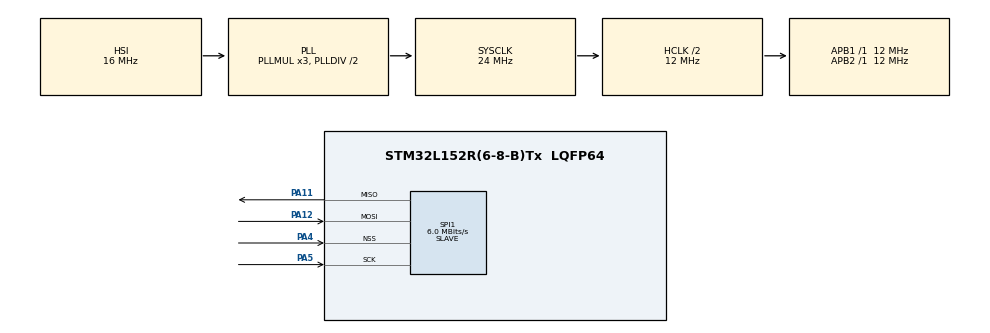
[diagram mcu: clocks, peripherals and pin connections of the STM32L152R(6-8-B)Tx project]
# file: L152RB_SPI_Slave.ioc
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Mcu.Family=STM32L1
Mcu.Name=STM32L152R(6-8-B)Tx
Mcu.Package=LQFP64
NVIC.PriorityGroup=NVIC_PRIORITYGROUP_4
NVIC.SPI1_IRQn=true\:0\:0\:false\:false\:true\:true\:true
PA11.Mode=Full_Duplex_Slave
PA11.Signal=SPI1_MISO
PA12.Mode=Full_Duplex_Slave
PA12.Signal=SPI1_MOSI
PA4.Mode=NSS_Signal_Hard_Input
PA4.Signal=SPI1_NSS
PA5.Mode=Full_Duplex_Slave
PA5.Signal=SPI1_SCK
ProjectManager.HeapSize=0x200
ProjectManager.StackSize=0x400
ProjectManager.TargetToolchain=STM32CubeIDE
RCC.AHBCLKDivider=RCC_SYSCLK_DIV2
RCC.AHBFreq_Value=12000000
RCC.APB1Freq_Value=12000000
RCC.APB1TimFreq_Value=12000000
RCC.APB2Freq_Value=12000000
RCC.APB2TimFreq_Value=12000000
RCC.HCLKFreq_Value=12000000
RCC.HSE_VALUE=24000000
RCC.HSI_VALUE=16000000
RCC.LSE_VALUE=32768
RCC.MSI_VALUE=2097000
RCC.SYSCLKFreq_VALUE=24000000
RCC.SYSCLKSource=RCC_SYSCLKSOURCE_PLLCLK
RCC.VCOOutputFreq_Value=48000000
SPI1.CalculateBaudRate=6.0 MBits/s
SPI1.Direction=SPI_DIRECTION_2LINES
SPI1.Mode=SPI_MODE_SLAVE
SPI1.VirtualNSS=VM_NSSHARD
SPI1.VirtualType=VM_SLAVE
board=custom

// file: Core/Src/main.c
/* USER CODE BEGIN Header */
/**
  ******************************************************************************
  * @file           : main.c
  * @brief          : Main program body
  ******************************************************************************
  * @attention
  *
  * <h2><center>&copy; Copyright (c) 2020 STMicroelectronics.
  * All rights reserved.</center></h2>
  *
  * This software component is licensed by ST under BSD 3-Clause license,
  * the "License"; You may not use this file except in compliance with the
  * License. You may obtain a copy of the License at:
  *                        opensource.org/licenses/BSD-3-Clause
  *
  ******************************************************************************
  */
/* USER CODE END Header */
#include "main.h"

SPI_HandleTypeDef hspi1;
uint8_t pData = 0;

void SystemClock_Config(void);
static void MX_GPIO_Init(void);
static void MX_SPI1_Init(void);

int main(void)
{
	HAL_Init();

	SystemClock_Config();

	MX_GPIO_Init();
	MX_SPI1_Init();

	HAL_SPI_Receive_IT(&hspi1, &pData, 1);

	while (1)
	{
		//HAL_SPI_Receive_IT(&hspi1, &pData, 1);
		HAL_GPIO_TogglePin(GPIOB, GPIO_PIN_6);
		HAL_Delay(500);
	}
}

void HAL_SPI_TxRxCpltCallback(SPI_HandleTypeDef *hspi)
{
	HAL_GPIO_TogglePin(GPIOB, GPIO_PIN_7);
	if(hspi->Instance == hspi1.Instance)
	{
		HAL_SPI_Receive_IT(&hspi1, &pData, 1);
	}
}

void SystemClock_Config(void)
{
  RCC_OscInitTypeDef RCC_OscInitStruct = {0};
  RCC_ClkInitTypeDef RCC_ClkInitStruct = {0};

  /** Configure the main internal regulator output voltage
  */
  __HAL_PWR_VOLTAGESCALING_CONFIG(PWR_REGULATOR_VOLTAGE_SCALE1);
  /** Initializes the RCC Oscillators according to the specified parameters
  * in the RCC_OscInitTypeDef structure.
  */
  RCC_OscInitStruct.OscillatorType = RCC_OSCILLATORTYPE_HSI;
  RCC_OscInitStruct.HSIState = RCC_HSI_ON;
  RCC_OscInitStruct.HSICalibrationValue = RCC_HSICALIBRATION_DEFAULT;
  RCC_OscInitStruct.PLL.PLLState = RCC_PLL_ON;
  RCC_OscInitStruct.PLL.PLLSource = RCC_PLLSOURCE_HSI;
  RCC_OscInitStruct.PLL.PLLMUL = RCC_PLL_MUL3;
  RCC_OscInitStruct.PLL.PLLDIV = RCC_PLL_DIV2;
  if (HAL_RCC_OscConfig(&RCC_OscInitStruct) != HAL_OK)
  {
    Error_Handler();
  }
  /** Initializes the CPU, AHB and APB buses clocks
  */
  RCC_ClkInitStruct.ClockType = RCC_CLOCKTYPE_HCLK|RCC_CLOCKTYPE_SYSCLK
                              |RCC_CLOCKTYPE_PCLK1|RCC_CLOCKTYPE_PCLK2;
  RCC_ClkInitStruct.SYSCLKSource = RCC_SYSCLKSOURCE_PLLCLK;
  RCC_ClkInitStruct.AHBCLKDivider = RCC_SYSCLK_DIV2;
  RCC_ClkInitStruct.APB1CLKDivider = RCC_HCLK_DIV1;
  RCC_ClkInitStruct.APB2CLKDivider = RCC_HCLK_DIV1;

  if (HAL_RCC_ClockConfig(&RCC_ClkInitStruct, FLASH_LATENCY_0) != HAL_OK)
  {
    Error_Handler();
  }
}

static void MX_SPI1_Init(void)
{
  hspi1.Instance = SPI1;
  hspi1.Init.Mode = SPI_MODE_SLAVE;
  hspi1.Init.Direction = SPI_DIRECTION_2LINES;
  hspi1.Init.DataSize = SPI_DATASIZE_8BIT;
  hspi1.Init.CLKPolarity = SPI_POLARITY_LOW;
  hspi1.Init.CLKPhase = SPI_PHASE_1EDGE;
  hspi1.Init.NSS = SPI_NSS_HARD_INPUT;
  hspi1.Init.BaudRatePrescaler = SPI_BAUDRATEPRESCALER_256;
  hspi1.Init.FirstBit = SPI_FIRSTBIT_MSB;
  hspi1.Init.TIMode = SPI_TIMODE_DISABLE;
  hspi1.Init.CRCCalculation = SPI_CRCCALCULATION_DISABLE;
  hspi1.Init.CRCPolynomial = 10;
  if (HAL_SPI_Init(&hspi1) != HAL_OK)
  {
    Error_Handler();
  }
}

static void MX_GPIO_Init(void)
{
	GPIO_InitTypeDef GPIO_InitStruct = {0};

	__HAL_RCC_GPIOA_CLK_ENABLE();
	__HAL_RCC_GPIOB_CLK_ENABLE();

	HAL_GPIO_WritePin(GPIOB, GPIO_PIN_6|GPIO_PIN_7, GPIO_PIN_SET);

	/*Configure GPIO pins : PB6 PB7 */
	GPIO_InitStruct.Pin = GPIO_PIN_6|GPIO_PIN_7;
	GPIO_InitStruct.Mode = GPIO_MODE_OUTPUT_PP;
	GPIO_InitStruct.Pull = GPIO_NOPULL;
	GPIO_InitStruct.Speed = GPIO_SPEED_FREQ_HIGH;
	HAL_GPIO_Init(GPIOB, &GPIO_InitStruct);
}

void Error_Handler(void)
{
}

/************************ (C) COPYRIGHT STMicroelectronics *****END OF FILE****/
